VERSION 5.8 ;
NAMESCASESENSITIVE ON ;
BUSBITCHARS "[]" ;
DIVIDERCHAR "/" ;

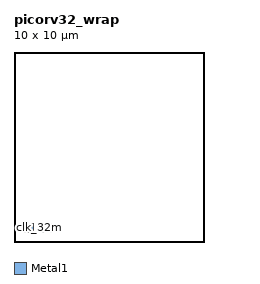
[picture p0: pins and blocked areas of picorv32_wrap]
MACRO picorv32_wrap
  CLASS BLOCK ;
  ORIGIN 0 0 ;
  SIZE 10.0 BY 10.0 ;
  SYMMETRY X Y ;
  PIN clk_32m
    DIRECTION INPUT ; USE SIGNAL ;
    PORT LAYER Metal1 ; RECT 0.5 0.5 1.0 1.0 ; END END
  END clk_32m
  PIN rst_n
    DIRECTION INPUT ; USE SIGNAL ;
    PORT LAYER Metal1 ; RECT 1.5 0.5 2.0 1.0 ; END END
  END rst_n
  PIN cpu_reset
    DIRECTION INPUT ; USE SIGNAL ;
    PORT LAYER Metal1 ; RECT 2.5 0.5 3.0 1.0 ; END END
  END cpu_reset
  PIN irq_in
    DIRECTION INPUT ; USE SIGNAL ;
    PORT LAYER Metal1 ; RECT 3.5 0.5 4.0 1.0 ; END END
  END irq_in
  PIN HREADY
    DIRECTION INPUT ; USE SIGNAL ;
    PORT LAYER Metal1 ; RECT 4.5 0.5 5.0 1.0 ; END END
  END HREADY
  PIN HRESP
    DIRECTION INPUT ; USE SIGNAL ;
    PORT LAYER Metal1 ; RECT 5.5 0.5 6.0 1.0 ; END END
  END HRESP
  PIN fw_ld_we
    DIRECTION INPUT ; USE SIGNAL ;
    PORT LAYER Metal1 ; RECT 6.5 0.5 7.0 1.0 ; END END
  END fw_ld_we
  PIN fw_ld_ready
    DIRECTION OUTPUT ; USE SIGNAL ;
    PORT LAYER Metal1 ; RECT 0.5 9.0 1.0 9.5 ; END END
  END fw_ld_ready
  PIN HWRITE
    DIRECTION OUTPUT ; USE SIGNAL ;
    PORT LAYER Metal1 ; RECT 1.5 9.0 2.0 9.5 ; END END
  END HWRITE
  BUS HRDATA
    BUSTYPE BUS ;
  END HRDATA
  BUS HWDATA
    BUSTYPE BUS ;
  END HWDATA
  BUS HADDR
    BUSTYPE BUS ;
  END HADDR
  BUS HTRANS
    BUSTYPE BUS ;
  END HTRANS
  BUS HSIZE
    BUSTYPE BUS ;
  END HSIZE
  BUS HBURST
    BUSTYPE BUS ;
  END HBURST
  BUS fw_ld_addr
    BUSTYPE BUS ;
  END fw_ld_addr
  BUS fw_ld_wdata
    BUSTYPE BUS ;
  END fw_ld_wdata
  BUS fw_ld_rdata
    BUSTYPE BUS ;
  END fw_ld_rdata
END picorv32_wrap

END LIBRARY
